VERSION 5.7 ;
  NOWIREEXTENSIONATPIN ON ;
  DIVIDERCHAR "/" ;
  BUSBITCHARS "[]" ;
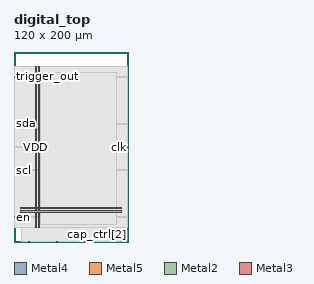
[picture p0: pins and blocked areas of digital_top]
MACRO digital_top
  CLASS BLOCK ;
  FOREIGN digital_top ;
  ORIGIN 0.000 0.000 ;
  SIZE 120.000 BY 200.000 ;
  PIN VDD
    DIRECTION INOUT ;
    USE POWER ;
    PORT
      LAYER Metal4 ;
        RECT 22.240 15.380 23.840 184.540 ;
    END
    PORT
      LAYER Metal5 ;
        RECT 6.720 31.530 113.120 33.130 ;
    END
  END VDD
  PIN VSS
    DIRECTION INOUT ;
    USE GROUND ;
    PORT
      LAYER Metal4 ;
        RECT 25.540 15.380 27.140 184.540 ;
    END
    PORT
      LAYER Metal5 ;
        RECT 6.720 34.830 113.120 36.430 ;
    END
  END VSS
  PIN cap_ctrl[0]
    DIRECTION OUTPUT ;
    USE SIGNAL ;
    ANTENNADIFFAREA 0.897600 ;
    PORT
      LAYER Metal2 ;
        RECT 44.800 0.000 45.360 0.560 ;
    END
  END cap_ctrl[0]
  PIN cap_ctrl[1]
    DIRECTION OUTPUT ;
    USE SIGNAL ;
    ANTENNADIFFAREA 0.897600 ;
    PORT
      LAYER Metal2 ;
        RECT 73.920 0.000 74.480 0.560 ;
    END
  END cap_ctrl[1]
  PIN cap_ctrl[2]
    DIRECTION OUTPUT ;
    USE SIGNAL ;
    ANTENNADIFFAREA 0.897600 ;
    PORT
      LAYER Metal2 ;
        RECT 103.040 0.000 103.600 0.560 ;
    END
  END cap_ctrl[2]
  PIN clk
    DIRECTION INPUT ;
    USE SIGNAL ;
    ANTENNAGATEAREA 4.738000 ;
    PORT
      LAYER Metal3 ;
        RECT 119.440 99.680 120.000 100.240 ;
    END
  END clk
  PIN comp_out
    DIRECTION INPUT ;
    USE SIGNAL ;
    ANTENNAGATEAREA 0.396000 ;
    PORT
      LAYER Metal2 ;
        RECT 15.680 0.000 16.240 0.560 ;
    END
  END comp_out
  PIN en
    DIRECTION INPUT ;
    USE SIGNAL ;
    ANTENNAGATEAREA 0.396000 ;
    PORT
      LAYER Metal3 ;
        RECT 0.000 25.760 0.560 26.320 ;
    END
  END en
  PIN scl
    DIRECTION INPUT ;
    USE SIGNAL ;
    ANTENNAGATEAREA 0.396000 ;
    PORT
      LAYER Metal3 ;
        RECT 0.000 75.040 0.560 75.600 ;
    END
  END scl
  PIN sda
    DIRECTION INOUT ;
    USE SIGNAL ;
    ANTENNAGATEAREA 1.366500 ;
    ANTENNADIFFAREA 2.080400 ;
    PORT
      LAYER Metal3 ;
        RECT 0.000 124.320 0.560 124.880 ;
    END
  END sda
  PIN trigger_out
    DIRECTION OUTPUT ;
    USE SIGNAL ;
    ANTENNADIFFAREA 0.897600 ;
    PORT
      LAYER Metal3 ;
        RECT 0.000 173.600 0.560 174.160 ;
    END
  END trigger_out
  OBS
      LAYER Nwell ;
        RECT 6.290 15.250 113.550 184.670 ;
      LAYER Metal1 ;
        RECT 6.720 15.380 113.120 184.540 ;
      LAYER Metal2 ;
        RECT 7.980 0.860 112.420 184.430 ;
        RECT 7.980 0.560 15.380 0.860 ;
        RECT 16.540 0.560 44.500 0.860 ;
        RECT 45.660 0.560 73.620 0.860 ;
        RECT 74.780 0.560 102.740 0.860 ;
        RECT 103.900 0.560 112.420 0.860 ;
      LAYER Metal3 ;
        RECT 0.560 174.460 119.440 184.380 ;
        RECT 0.860 173.300 119.440 174.460 ;
        RECT 0.560 125.180 119.440 173.300 ;
        RECT 0.860 124.020 119.440 125.180 ;
        RECT 0.560 100.540 119.440 124.020 ;
        RECT 0.560 99.380 119.140 100.540 ;
        RECT 0.560 75.900 119.440 99.380 ;
        RECT 0.860 74.740 119.440 75.900 ;
        RECT 0.560 26.620 119.440 74.740 ;
        RECT 0.860 25.460 119.440 26.620 ;
        RECT 0.560 15.540 119.440 25.460 ;
      LAYER Metal4 ;
        RECT 28.140 18.010 107.940 178.550 ;
  END
END digital_top
END LIBRARY

